VERSION 5.8 ;
BUSBITCHARS "[]" ;
DIVIDERCHAR "/" ;
UNITS
    DATABASE MICRONS 1000 ;
END UNITS

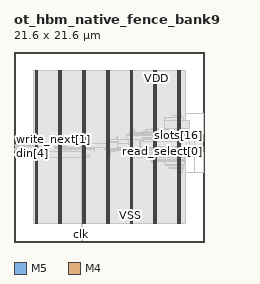
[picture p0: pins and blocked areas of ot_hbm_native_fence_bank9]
MACRO ot_hbm_native_fence_bank9
  FOREIGN ot_hbm_native_fence_bank9 0 0 ;
  CLASS BLOCK ;
  SIZE 21.6 BY 21.6 ;
  PIN clk
    DIRECTION INPUT ;
    USE SIGNAL ;
    PORT
      LAYER M5 ;
        RECT  7.632 0 7.656 0.084 ;
    END
  END clk
  PIN din[0]
    DIRECTION INPUT ;
    USE SIGNAL ;
    PORT
      LAYER M4 ;
        RECT  0 9.648 0.084 9.672 ;
    END
  END din[0]
  PIN din[1]
    DIRECTION INPUT ;
    USE SIGNAL ;
    PORT
      LAYER M4 ;
        RECT  0 9.744 0.084 9.768 ;
    END
  END din[1]
  PIN din[2]
    DIRECTION INPUT ;
    USE SIGNAL ;
    PORT
      LAYER M4 ;
        RECT  0 9.84 0.084 9.864 ;
    END
  END din[2]
  PIN din[3]
    DIRECTION INPUT ;
    USE SIGNAL ;
    PORT
      LAYER M4 ;
        RECT  0 9.936 0.084 9.96 ;
    END
  END din[3]
  PIN din[4]
    DIRECTION INPUT ;
    USE SIGNAL ;
    PORT
      LAYER M4 ;
        RECT  0 10.032 0.084 10.056 ;
    END
  END din[4]
  PIN din[5]
    DIRECTION INPUT ;
    USE SIGNAL ;
    PORT
      LAYER M4 ;
        RECT  0 10.128 0.084 10.152 ;
    END
  END din[5]
  PIN din[6]
    DIRECTION INPUT ;
    USE SIGNAL ;
    PORT
      LAYER M4 ;
        RECT  0 10.224 0.084 10.248 ;
    END
  END din[6]
  PIN din[7]
    DIRECTION INPUT ;
    USE SIGNAL ;
    PORT
      LAYER M4 ;
        RECT  0 10.32 0.084 10.344 ;
    END
  END din[7]
  PIN din[8]
    DIRECTION INPUT ;
    USE SIGNAL ;
    PORT
      LAYER M4 ;
        RECT  0 10.416 0.084 10.44 ;
    END
  END din[8]
  PIN read_next[0]
    DIRECTION INPUT ;
    USE SIGNAL ;
    PORT
      LAYER M4 ;
        RECT  0 10.512 0.084 10.536 ;
    END
  END read_next[0]
  PIN read_next[1]
    DIRECTION INPUT ;
    USE SIGNAL ;
    PORT
      LAYER M4 ;
        RECT  0 10.608 0.084 10.632 ;
    END
  END read_next[1]
  PIN read_select[0]
    DIRECTION OUTPUT ;
    USE SIGNAL ;
    PORT
      LAYER M4 ;
        RECT  21.516 10.32 21.6 10.344 ;
    END
  END read_select[0]
  PIN read_select[1]
    DIRECTION OUTPUT ;
    USE SIGNAL ;
    PORT
      LAYER M4 ;
        RECT  21.516 10.416 21.6 10.44 ;
    END
  END read_select[1]
  PIN rst_n
    DIRECTION INPUT ;
    USE SIGNAL ;
    PORT
      LAYER M5 ;
        RECT  7.728 0 7.752 0.084 ;
    END
  END rst_n
  PIN slots[0]
    DIRECTION OUTPUT ;
    USE SIGNAL ;
    PORT
      LAYER M4 ;
        RECT  21.516 10.512 21.6 10.536 ;
    END
  END slots[0]
  PIN slots[10]
    DIRECTION OUTPUT ;
    USE SIGNAL ;
    PORT
      LAYER M4 ;
        RECT  21.516 11.472 21.6 11.496 ;
    END
  END slots[10]
  PIN slots[11]
    DIRECTION OUTPUT ;
    USE SIGNAL ;
    PORT
      LAYER M4 ;
        RECT  21.516 11.568 21.6 11.592 ;
    END
  END slots[11]
  PIN slots[12]
    DIRECTION OUTPUT ;
    USE SIGNAL ;
    PORT
      LAYER M4 ;
        RECT  21.516 11.664 21.6 11.688 ;
    END
  END slots[12]
  PIN slots[13]
    DIRECTION OUTPUT ;
    USE SIGNAL ;
    PORT
      LAYER M4 ;
        RECT  21.516 11.76 21.6 11.784 ;
    END
  END slots[13]
  PIN slots[14]
    DIRECTION OUTPUT ;
    USE SIGNAL ;
    PORT
      LAYER M4 ;
        RECT  21.516 11.856 21.6 11.88 ;
    END
  END slots[14]
  PIN slots[15]
    DIRECTION OUTPUT ;
    USE SIGNAL ;
    PORT
      LAYER M4 ;
        RECT  21.516 11.952 21.6 11.976 ;
    END
  END slots[15]
  PIN slots[16]
    DIRECTION OUTPUT ;
    USE SIGNAL ;
    PORT
      LAYER M4 ;
        RECT  21.516 12.048 21.6 12.072 ;
    END
  END slots[16]
  PIN slots[17]
    DIRECTION OUTPUT ;
    USE SIGNAL ;
    PORT
      LAYER M4 ;
        RECT  21.516 12.144 21.6 12.168 ;
    END
  END slots[17]
  PIN slots[1]
    DIRECTION OUTPUT ;
    USE SIGNAL ;
    PORT
      LAYER M4 ;
        RECT  21.516 10.608 21.6 10.632 ;
    END
  END slots[1]
  PIN slots[2]
    DIRECTION OUTPUT ;
    USE SIGNAL ;
    PORT
      LAYER M4 ;
        RECT  21.516 10.704 21.6 10.728 ;
    END
  END slots[2]
  PIN slots[3]
    DIRECTION OUTPUT ;
    USE SIGNAL ;
    PORT
      LAYER M4 ;
        RECT  21.516 10.8 21.6 10.824 ;
    END
  END slots[3]
  PIN slots[4]
    DIRECTION OUTPUT ;
    USE SIGNAL ;
    PORT
      LAYER M4 ;
        RECT  21.516 10.896 21.6 10.92 ;
    END
  END slots[4]
  PIN slots[5]
    DIRECTION OUTPUT ;
    USE SIGNAL ;
    PORT
      LAYER M4 ;
        RECT  21.516 10.992 21.6 11.016 ;
    END
  END slots[5]
  PIN slots[6]
    DIRECTION OUTPUT ;
    USE SIGNAL ;
    PORT
      LAYER M4 ;
        RECT  21.516 11.088 21.6 11.112 ;
    END
  END slots[6]
  PIN slots[7]
    DIRECTION OUTPUT ;
    USE SIGNAL ;
    PORT
      LAYER M4 ;
        RECT  21.516 11.184 21.6 11.208 ;
    END
  END slots[7]
  PIN slots[8]
    DIRECTION OUTPUT ;
    USE SIGNAL ;
    PORT
      LAYER M4 ;
        RECT  21.516 11.28 21.6 11.304 ;
    END
  END slots[8]
  PIN slots[9]
    DIRECTION OUTPUT ;
    USE SIGNAL ;
    PORT
      LAYER M4 ;
        RECT  21.516 11.376 21.6 11.4 ;
    END
  END slots[9]
  PIN write_next[0]
    DIRECTION INPUT ;
    USE SIGNAL ;
    PORT
      LAYER M4 ;
        RECT  0 10.704 0.084 10.728 ;
    END
  END write_next[0]
  PIN write_next[1]
    DIRECTION INPUT ;
    USE SIGNAL ;
    PORT
      LAYER M4 ;
        RECT  0 10.8 0.084 10.824 ;
    END
  END write_next[1]
  PIN VDD
    DIRECTION INOUT ;
    USE POWER ;
    PORT
      LAYER M5 ;
        RECT  18.792 2.151 18.912 19.449 ;
        RECT  16.092 2.151 16.212 19.449 ;
        RECT  13.392 2.151 13.512 19.449 ;
        RECT  10.692 2.151 10.812 19.449 ;
        RECT  7.992 2.151 8.112 19.449 ;
        RECT  5.292 2.151 5.412 19.449 ;
        RECT  2.592 2.151 2.712 19.449 ;
    END
  END VDD
  PIN VSS
    DIRECTION INOUT ;
    USE GROUND ;
    PORT
      LAYER M5 ;
        RECT  18.6 2.137 18.72 19.463 ;
        RECT  15.9 2.137 16.02 19.463 ;
        RECT  13.2 2.137 13.32 19.463 ;
        RECT  10.5 2.137 10.62 19.463 ;
        RECT  7.8 2.137 7.92 19.463 ;
        RECT  5.1 2.137 5.22 19.463 ;
        RECT  2.4 2.137 2.52 19.463 ;
    END
  END VSS
  # OT_OBS_CLOSED layer=M5 d_um=1.536 added=1
  OBS
    LAYER RVTN ;
     RECT  2.16 2.16 19.44 2.295 ;
     RECT  2.16 2.565 19.44 2.835 ;
     RECT  2.16 3.105 19.44 3.375 ;
     RECT  2.16 3.645 19.44 3.915 ;
     RECT  2.16 4.185 19.44 4.455 ;
     RECT  2.16 4.725 19.44 4.995 ;
     RECT  2.16 5.265 19.44 5.535 ;
     RECT  2.16 5.805 19.44 6.075 ;
     RECT  2.16 6.345 19.44 6.615 ;
     RECT  2.16 6.885 19.44 7.155 ;
     RECT  2.16 7.425 19.44 7.695 ;
     RECT  2.16 7.965 19.44 8.235 ;
     RECT  2.16 8.505 19.44 8.775 ;
     RECT  2.16 9.045 19.44 9.315 ;
     RECT  2.16 9.585 19.44 9.855 ;
     RECT  2.16 10.125 19.44 10.395 ;
     RECT  2.16 10.665 19.44 10.935 ;
     RECT  2.16 11.205 19.44 11.475 ;
     RECT  2.16 11.745 19.44 12.015 ;
     RECT  2.16 12.285 19.44 12.555 ;
     RECT  2.16 12.825 19.44 13.095 ;
     RECT  2.16 13.365 19.44 13.635 ;
     RECT  2.16 13.905 19.44 14.175 ;
     RECT  2.16 14.445 19.44 14.715 ;
     RECT  2.16 14.985 19.44 15.255 ;
     RECT  2.16 15.525 19.44 15.795 ;
     RECT  2.16 16.065 19.44 16.335 ;
     RECT  2.16 16.605 19.44 16.875 ;
     RECT  2.16 17.145 19.44 17.415 ;
     RECT  2.16 17.685 19.44 17.955 ;
     RECT  2.16 18.225 19.44 18.495 ;
     RECT  2.16 18.765 19.44 19.035 ;
     RECT  2.16 19.305 19.44 19.44 ;
    LAYER RVTP ;
     RECT  2.16 2.295 19.44 2.565 ;
     RECT  2.16 2.835 19.44 3.105 ;
     RECT  2.16 3.375 19.44 3.645 ;
     RECT  2.16 3.915 19.44 4.185 ;
     RECT  2.16 4.455 19.44 4.725 ;
     RECT  2.16 4.995 19.44 5.265 ;
     RECT  2.16 5.535 19.44 5.805 ;
     RECT  2.16 6.075 19.44 6.345 ;
     RECT  2.16 6.615 19.44 6.885 ;
     RECT  2.16 7.155 19.44 7.425 ;
     RECT  2.16 7.695 19.44 7.965 ;
     RECT  2.16 8.235 19.44 8.505 ;
     RECT  2.16 8.775 19.44 9.045 ;
     RECT  2.16 9.315 19.44 9.585 ;
     RECT  2.16 9.855 19.44 10.125 ;
     RECT  2.16 10.395 19.44 10.665 ;
     RECT  2.16 10.935 19.44 11.205 ;
     RECT  2.16 11.475 19.44 11.745 ;
     RECT  2.16 12.015 19.44 12.285 ;
     RECT  2.16 12.555 19.44 12.825 ;
     RECT  2.16 13.095 19.44 13.365 ;
     RECT  2.16 13.635 19.44 13.905 ;
     RECT  2.16 14.175 19.44 14.445 ;
     RECT  2.16 14.715 19.44 14.985 ;
     RECT  2.16 15.255 19.44 15.525 ;
     RECT  2.16 15.795 19.44 16.065 ;
     RECT  2.16 16.335 19.44 16.605 ;
     RECT  2.16 16.875 19.44 17.145 ;
     RECT  2.16 17.415 19.44 17.685 ;
     RECT  2.16 17.955 19.44 18.225 ;
     RECT  2.16 18.495 19.44 18.765 ;
     RECT  2.16 19.035 19.44 19.305 ;
    LAYER M1 ;
     RECT  2.16 2.151 19.44 19.449 ;
    LAYER M2 ;
     RECT  0.103 10.944 0.139 10.962 ;
     RECT  0.103 9.828 0.203 9.846 ;
     RECT  0.139 10.944 2.16 11.034 ;
     RECT  2.16 2.151 19.44 19.449 ;
     RECT  19.44 10.638 19.931 12.204 ;
     RECT  19.44 13.806 19.931 13.824 ;
     RECT  19.931 11.016 20.435 12.204 ;
     RECT  20.435 11.106 20.471 12.204 ;
     RECT  20.471 11.106 20.507 11.124 ;
     RECT  20.471 11.916 20.507 12.204 ;
     RECT  19.44 7.866 20.543 7.956 ;
     RECT  20.507 12.186 21.479 12.204 ;
     RECT  20.543 7.866 21.515 7.884 ;
     RECT  19.44 14.616 21.515 14.634 ;
    LAYER M3 ;
     RECT  7.704 2.011 7.722 2.143 ;
     RECT  2.415 2.143 2.505 2.413 ;
     RECT  5.115 2.143 5.205 2.413 ;
     RECT  7.704 2.143 7.905 2.413 ;
     RECT  10.515 2.143 10.605 2.413 ;
     RECT  13.215 2.143 13.305 2.413 ;
     RECT  15.915 2.143 16.005 2.413 ;
     RECT  18.615 2.143 18.705 2.413 ;
     RECT  7.704 2.413 8.097 4.955 ;
     RECT  18.615 2.413 18.897 7.861 ;
     RECT  18.615 7.861 19.206 8.311 ;
     RECT  17.64 8.311 19.242 8.509 ;
     RECT  17.64 8.509 19.314 8.671 ;
     RECT  17.208 8.671 19.314 8.815 ;
     RECT  17.1 8.815 19.314 8.851 ;
     RECT  15.915 2.413 16.197 9.085 ;
     RECT  15.588 9.085 16.197 9.121 ;
     RECT  17.1 8.851 19.35 9.121 ;
     RECT  15.588 9.121 19.35 9.319 ;
     RECT  15.552 9.319 19.35 9.355 ;
     RECT  10.515 2.413 10.797 9.391 ;
     RECT  7.776 4.955 8.097 9.589 ;
     RECT  13.215 2.413 13.497 9.625 ;
     RECT  15.516 9.355 19.35 9.625 ;
     RECT  2.415 2.413 2.697 9.643 ;
     RECT  5.115 2.413 5.397 9.643 ;
     RECT  7.776 9.589 8.622 9.643 ;
     RECT  13.215 9.625 14.202 9.661 ;
     RECT  15.444 9.625 19.35 9.661 ;
     RECT  2.304 9.643 2.697 9.689 ;
     RECT  5.004 9.643 5.397 9.689 ;
     RECT  10.515 9.391 10.854 9.751 ;
     RECT  7.704 9.643 8.622 9.779 ;
     RECT  7.704 9.779 8.154 9.787 ;
     RECT  0.18 9.595 0.198 9.82 ;
     RECT  6.768 9.823 6.786 9.883 ;
     RECT  0.108 9.82 0.198 9.917 ;
     RECT  6.444 9.883 6.786 9.931 ;
     RECT  7.632 9.787 8.154 9.931 ;
     RECT  13.215 9.661 19.35 9.931 ;
     RECT  5.04 9.689 5.397 10.123 ;
     RECT  12.888 9.931 19.35 10.129 ;
     RECT  12.42 10.129 19.35 10.201 ;
     RECT  2.415 9.689 2.697 10.291 ;
     RECT  3.492 10.021 3.51 10.291 ;
     RECT  10.515 9.751 10.926 10.327 ;
     RECT  20.52 7.933 20.538 10.349 ;
     RECT  10.515 10.327 11.502 10.363 ;
     RECT  12.42 10.201 19.386 10.363 ;
     RECT  2.415 10.291 3.51 10.435 ;
     RECT  9.108 10.327 9.126 10.435 ;
     RECT  10.515 10.363 19.386 10.471 ;
     RECT  21.492 7.861 21.51 10.541 ;
     RECT  5.04 10.123 5.706 10.561 ;
     RECT  6.444 9.931 8.154 10.561 ;
     RECT  9.108 10.435 9.198 10.561 ;
     RECT  2.304 10.435 3.51 10.589 ;
     RECT  5.04 10.561 9.198 10.589 ;
     RECT  10.296 10.471 19.386 10.603 ;
     RECT  5.04 10.589 8.586 10.669 ;
     RECT  10.296 10.603 20.502 10.697 ;
     RECT  9.324 10.699 9.342 10.739 ;
     RECT  4.572 10.669 8.586 10.769 ;
     RECT  2.304 10.589 3.402 10.795 ;
     RECT  4.572 10.769 6.246 10.859 ;
     RECT  9.468 10.741 9.486 10.859 ;
     RECT  2.268 10.795 3.402 10.895 ;
     RECT  4.572 10.859 5.742 10.895 ;
     RECT  7.164 10.769 8.586 10.895 ;
     RECT  0.108 9.917 0.162 10.967 ;
     RECT  0.144 10.967 0.162 11.039 ;
     RECT  2.304 10.895 3.402 11.129 ;
     RECT  5.115 10.895 5.742 11.129 ;
     RECT  2.304 11.129 2.697 11.165 ;
     RECT  5.115 11.129 5.562 11.165 ;
     RECT  7.164 10.895 8.097 11.165 ;
     RECT  10.515 10.697 20.502 11.405 ;
     RECT  7.344 11.165 8.097 11.579 ;
     RECT  10.515 11.405 19.314 11.669 ;
     RECT  10.515 11.669 11.934 11.705 ;
     RECT  10.515 11.705 10.854 11.813 ;
     RECT  11.628 11.705 11.754 11.939 ;
     RECT  20.448 11.405 20.502 11.939 ;
     RECT  11.628 11.939 11.646 11.975 ;
     RECT  21.492 11.947 21.51 12.043 ;
     RECT  12.744 11.669 19.314 12.139 ;
     RECT  21.456 12.043 21.51 12.209 ;
     RECT  12.744 12.139 19.926 12.245 ;
     RECT  13.14 12.245 19.926 12.281 ;
     RECT  13.176 12.281 19.926 12.479 ;
     RECT  13.176 12.479 13.698 12.515 ;
     RECT  14.652 12.479 19.926 12.515 ;
     RECT  13.215 12.515 13.698 12.749 ;
     RECT  14.94 12.515 19.926 12.749 ;
     RECT  13.215 12.749 13.554 12.785 ;
     RECT  15.624 12.749 19.926 12.893 ;
     RECT  15.876 12.893 19.926 12.929 ;
     RECT  15.876 12.929 16.197 13.055 ;
     RECT  17.064 12.929 19.926 13.829 ;
     RECT  17.064 13.829 19.314 14.099 ;
     RECT  18 14.099 19.134 14.135 ;
     RECT  17.1 14.099 17.118 14.171 ;
     RECT  18 14.135 18.99 14.405 ;
     RECT  18.54 14.405 18.99 14.441 ;
     RECT  21.492 12.209 21.51 14.639 ;
     RECT  18.54 14.441 18.897 14.675 ;
     RECT  2.415 11.165 2.697 19.187 ;
     RECT  5.115 11.165 5.397 19.187 ;
     RECT  7.815 11.579 8.097 19.187 ;
     RECT  10.515 11.813 10.797 19.187 ;
     RECT  13.215 12.785 13.497 19.187 ;
     RECT  15.915 13.055 16.197 19.187 ;
     RECT  18.615 14.675 18.897 19.187 ;
     RECT  2.415 19.187 2.505 19.457 ;
     RECT  5.115 19.187 5.205 19.457 ;
     RECT  7.815 19.187 7.905 19.457 ;
     RECT  10.515 19.187 10.605 19.457 ;
     RECT  13.215 19.187 13.305 19.457 ;
     RECT  15.915 19.187 16.005 19.457 ;
     RECT  18.615 19.187 18.705 19.457 ;
    LAYER M4 ;
     RECT  0.06 9.648 0.169 10.824 ;
     RECT  0.169 9.6 0.253 10.824 ;
     RECT  0.253 9.648 2.408 10.824 ;
     RECT  2.408 2.148 2.512 19.452 ;
     RECT  2.512 2.418 2.704 19.182 ;
     RECT  2.704 9.648 5.108 10.344 ;
     RECT  5.108 2.148 5.212 19.452 ;
     RECT  5.212 2.418 5.404 19.182 ;
     RECT  5.404 9.648 7.621 10.344 ;
     RECT  7.676 2.016 7.763 2.04 ;
     RECT  7.621 9.648 7.808 11.208 ;
     RECT  7.808 2.148 7.912 19.452 ;
     RECT  7.912 2.418 8.104 19.182 ;
     RECT  8.104 10.704 10.508 11.208 ;
     RECT  10.508 2.148 10.612 19.452 ;
     RECT  10.612 2.418 10.804 19.182 ;
     RECT  10.804 10.608 11.801 11.304 ;
     RECT  11.801 11.184 11.833 11.304 ;
     RECT  11.833 11.184 13.057 11.688 ;
     RECT  13.057 11.136 13.208 11.688 ;
     RECT  13.208 2.148 13.312 19.452 ;
     RECT  13.312 2.418 13.504 19.182 ;
     RECT  13.504 9.648 14.257 11.688 ;
     RECT  14.257 10.56 14.429 11.688 ;
     RECT  14.429 11.424 14.641 11.688 ;
     RECT  14.641 11.424 14.717 11.832 ;
     RECT  14.717 11.808 15.793 11.832 ;
     RECT  15.793 11.808 15.908 11.976 ;
     RECT  15.908 2.148 16.012 19.452 ;
     RECT  16.012 2.418 16.204 19.182 ;
     RECT  16.204 11.952 16.697 11.976 ;
     RECT  16.204 9.792 17.123 10.872 ;
     RECT  17.123 10.848 17.129 10.872 ;
     RECT  17.123 9.792 17.269 9.816 ;
     RECT  17.269 9.216 17.453 9.816 ;
     RECT  17.453 9.216 17.489 9.24 ;
     RECT  18.608 2.148 18.712 19.452 ;
     RECT  18.712 2.418 18.904 19.182 ;
     RECT  18.904 10.416 19.897 11.88 ;
     RECT  19.897 10.416 20.509 12.168 ;
     RECT  20.509 10.32 21.564 12.168 ;
    LAYER M5 ;
     RECT  7.632 0.016 7.752 2.137 ;
     RECT  2.4 2.137 2.52 2.151 ;
     RECT  5.1 2.137 5.22 2.151 ;
     RECT  7.632 2.137 7.92 2.151 ;
     RECT  10.5 2.137 10.62 2.151 ;
     RECT  13.2 2.137 13.32 2.151 ;
     RECT  15.9 2.137 16.02 2.151 ;
     RECT  18.6 2.137 18.72 2.151 ;
     RECT  13.2 2.151 13.512 9.637 ;
     RECT  0.192 9.589 0.216 9.827 ;
     RECT  15.9 2.151 16.212 10.741 ;
     RECT  15.9 10.741 17.112 10.883 ;
     RECT  7.632 2.151 8.112 11.219 ;
     RECT  13.2 9.637 14.232 11.699 ;
     RECT  2.4 2.151 2.712 19.449 ;
     RECT  5.1 2.151 5.412 19.449 ;
     RECT  7.8 11.219 8.112 19.449 ;
     RECT  10.5 2.151 10.812 19.449 ;
     RECT  13.2 11.699 13.512 19.449 ;
     RECT  15.9 10.883 16.212 19.449 ;
     RECT  18.6 2.151 18.912 19.449 ;
     RECT  2.4 19.449 2.52 19.463 ;
     RECT  5.1 19.449 5.22 19.463 ;
     RECT  7.8 19.449 7.92 19.463 ;
     RECT  10.5 19.449 10.62 19.463 ;
     RECT  13.2 19.449 13.32 19.463 ;
     RECT  15.9 19.449 16.02 19.463 ;
     RECT  18.6 19.449 18.72 19.463 ;
     RECT  17.112 10.741 18.6 10.883 ;
  END
END ot_hbm_native_fence_bank9
END LIBRARY
